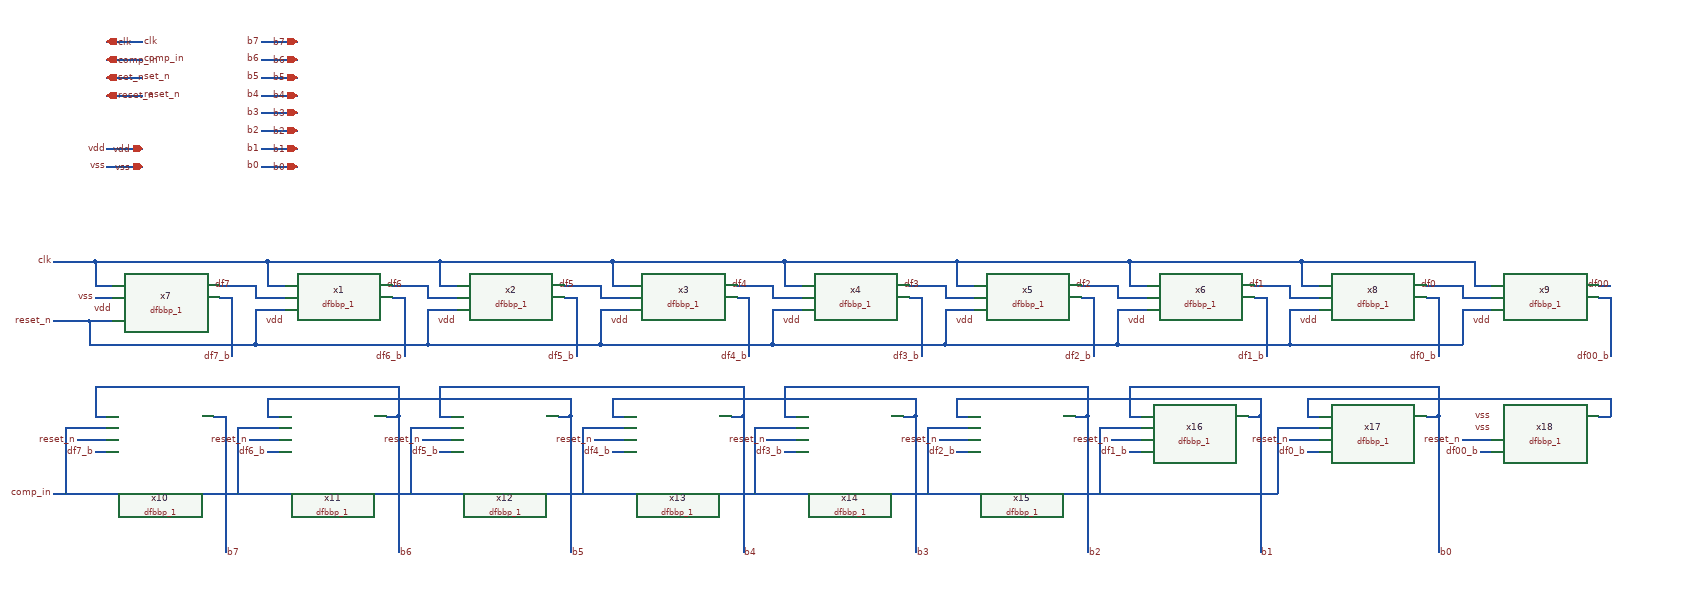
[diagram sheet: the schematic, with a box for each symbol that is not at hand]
v {xschem version=3.4.6RC file_version=1.2
}
G {}
K {}
V {}
S {}
E {}
N 380 -670 410 -670 {lab=clk}
N 380 -710 380 -670 {lab=clk}
N 380 -710 670 -710 {lab=clk}
N 380 -650 410 -650 {lab=vss}
N 370 -610 410 -610 {lab=#net1}
N 370 -610 370 -570 {lab=#net1}
N 650 -630 700 -630 {lab=#net1}
N 370 -570 650 -570 {lab=#net1}
N 650 -630 650 -570 {lab=#net1}
N 670 -670 700 -670 {lab=clk}
N 670 -710 670 -670 {lab=clk}
N 650 -650 700 -650 {lab=df7}
N 650 -670 650 -650 {lab=df7}
N 590 -670 650 -670 {lab=df7}
N 2100 -630 2150 -630 {lab=#net1}
N 2100 -630 2100 -570 {lab=#net1}
N 2120 -670 2150 -670 {lab=clk}
N 2120 -710 2120 -670 {lab=clk}
N 2100 -650 2150 -650 {lab=df2}
N 2100 -670 2100 -650 {lab=df2}
N 880 -670 940 -670 {lab=df6}
N 2390 -630 2440 -630 {lab=#net1}
N 2390 -630 2390 -570 {lab=#net1}
N 2410 -670 2440 -670 {lab=clk}
N 2410 -710 2410 -670 {lab=clk}
N 2390 -650 2440 -650 {lab=df1}
N 2390 -670 2390 -650 {lab=df1}
N 2330 -670 2390 -670 {lab=df1}
N 2680 -630 2730 -630 {lab=#net1}
N 2680 -630 2680 -570 {lab=#net1}
N 2700 -670 2730 -670 {lab=clk}
N 2700 -710 2700 -670 {lab=clk}
N 2680 -650 2730 -650 {lab=df0}
N 2680 -670 2680 -650 {lab=df0}
N 2620 -670 2680 -670 {lab=df0}
N 670 -710 960 -710 {lab=clk}
N 2120 -710 2410 -710 {lab=clk}
N 2410 -710 2700 -710 {lab=clk}
N 650 -570 940 -570 {lab=#net1}
N 2100 -570 2390 -570 {lab=#net1}
N 2390 -570 2680 -570 {lab=#net1}
N 590 -650 610 -650 {lab=df7_b}
N 610 -650 610 -550 {lab=df7_b}
N 880 -650 900 -650 {lab=df6_b}
N 900 -650 900 -550 {lab=df6_b}
N 2330 -650 2350 -650 {lab=df1_b}
N 2350 -650 2350 -550 {lab=df1_b}
N 2620 -650 2640 -650 {lab=df0_b}
N 2640 -650 2640 -550 {lab=df0_b}
N 2910 -650 2930 -650 {lab=df00_b}
N 2930 -650 2930 -550 {lab=df00_b}
N 2910 -670 2930 -670 {lab=df00}
N 940 -630 990 -630 {lab=#net1}
N 940 -630 940 -570 {lab=#net1}
N 960 -670 990 -670 {lab=clk}
N 960 -710 960 -670 {lab=clk}
N 940 -650 990 -650 {lab=df6}
N 940 -670 940 -650 {lab=df6}
N 1170 -670 1230 -670 {lab=df5}
N 960 -710 1250 -710 {lab=clk}
N 940 -570 1230 -570 {lab=#net1}
N 1170 -650 1190 -650 {lab=df5_b}
N 1190 -650 1190 -550 {lab=df5_b}
N 1230 -630 1280 -630 {lab=#net1}
N 1230 -630 1230 -570 {lab=#net1}
N 1250 -670 1280 -670 {lab=clk}
N 1250 -710 1250 -670 {lab=clk}
N 1230 -650 1280 -650 {lab=df5}
N 1230 -670 1230 -650 {lab=df5}
N 1460 -670 1520 -670 {lab=df4}
N 1250 -710 1540 -710 {lab=clk}
N 1230 -570 1520 -570 {lab=#net1}
N 1460 -650 1480 -650 {lab=df4_b}
N 1480 -650 1480 -550 {lab=df4_b}
N 1520 -630 1570 -630 {lab=#net1}
N 1520 -630 1520 -570 {lab=#net1}
N 1540 -670 1570 -670 {lab=clk}
N 1540 -710 1540 -670 {lab=clk}
N 1520 -650 1570 -650 {lab=df4}
N 1520 -670 1520 -650 {lab=df4}
N 1750 -670 1810 -670 {lab=df3}
N 1540 -710 1830 -710 {lab=clk}
N 1520 -570 1810 -570 {lab=#net1}
N 1750 -650 1770 -650 {lab=df3_b}
N 1770 -650 1770 -550 {lab=df3_b}
N 1810 -630 1860 -630 {lab=#net1}
N 1810 -630 1810 -570 {lab=#net1}
N 1830 -670 1860 -670 {lab=clk}
N 1830 -710 1830 -670 {lab=clk}
N 1810 -650 1860 -650 {lab=df3}
N 1810 -670 1810 -650 {lab=df3}
N 2040 -670 2100 -670 {lab=df2}
N 1830 -710 2120 -710 {lab=clk}
N 1810 -570 2100 -570 {lab=#net1}
N 2040 -650 2060 -650 {lab=df2_b}
N 2060 -650 2060 -550 {lab=df2_b}
N 2710 -390 2730 -390 {lab=df00_b}
N 2910 -450 2930 -450 {lab=#net2}
N 2930 -480 2930 -450 {lab=#net2}
N 2420 -450 2440 -450 {lab=#net2}
N 2420 -480 2420 -450 {lab=#net2}
N 2420 -390 2440 -390 {lab=df0_b}
N 2620 -450 2640 -450 {lab=b0}
N 2640 -500 2640 -450 {lab=b0}
N 2120 -500 2120 -450 {lab=b0}
N 2120 -450 2140 -450 {lab=b0}
N 2120 -500 2640 -500 {lab=b0}
N 2320 -450 2340 -450 {lab=b1}
N 2340 -480 2340 -450 {lab=b1}
N 1830 -450 1850 -450 {lab=b1}
N 1830 -480 1830 -450 {lab=b1}
N 1830 -480 2340 -480 {lab=b1}
N 2030 -450 2050 -450 {lab=b2}
N 2050 -500 2050 -450 {lab=b2}
N 1540 -450 1560 -450 {lab=b2}
N 1540 -500 1540 -450 {lab=b2}
N 1540 -500 2050 -500 {lab=b2}
N 1540 -390 1560 -390 {lab=df3_b}
N 1830 -390 1850 -390 {lab=df2_b}
N 2120 -390 2140 -390 {lab=df1_b}
N 1490 -430 1490 -320 {lab=comp_in}
N 1780 -430 1780 -320 {lab=comp_in}
N 1740 -450 1760 -450 {lab=b3}
N 1480 -320 1770 -320 {lab=comp_in}
N 2070 -430 2070 -320 {lab=comp_in}
N 1770 -320 2060 -320 {lab=comp_in}
N 2370 -430 2370 -320 {lab=comp_in}
N 2060 -320 2360 -320 {lab=comp_in}
N 1250 -450 1270 -450 {lab=b3}
N 1250 -480 1250 -450 {lab=b3}
N 1250 -480 1760 -480 {lab=b3}
N 1450 -450 1470 -450 {lab=b4}
N 1470 -500 1470 -450 {lab=b4}
N 960 -450 980 -450 {lab=b4}
N 960 -500 960 -450 {lab=b4}
N 960 -500 1470 -500 {lab=b4}
N 960 -390 980 -390 {lab=df5_b}
N 1250 -390 1270 -390 {lab=df4_b}
N 1200 -430 1200 -320 {lab=comp_in}
N 1160 -450 1180 -450 {lab=b5}
N 900 -320 1190 -320 {lab=comp_in}
N 1760 -480 1760 -450 {lab=b3}
N 1190 -320 1480 -320 {lab=comp_in}
N 910 -430 910 -320 {lab=comp_in}
N 670 -450 690 -450 {lab=b5}
N 670 -480 670 -450 {lab=b5}
N 670 -480 1180 -480 {lab=b5}
N 870 -450 890 -450 {lab=b6}
N 890 -500 890 -450 {lab=b6}
N 380 -450 400 -450 {lab=b6}
N 380 -500 380 -450 {lab=b6}
N 380 -500 890 -500 {lab=b6}
N 380 -390 400 -390 {lab=df7_b}
N 670 -390 690 -390 {lab=df6_b}
N 330 -430 330 -320 {lab=comp_in}
N 310 -320 320 -320 {lab=comp_in}
N 580 -450 600 -450 {lab=b7}
N 320 -320 610 -320 {lab=comp_in}
N 1180 -480 1180 -450 {lab=b5}
N 610 -320 900 -320 {lab=comp_in}
N 620 -430 620 -320 {lab=comp_in}
N 640 -410 690 -410 {lab=reset_n}
N 620 -430 690 -430 {lab=comp_in}
N 600 -450 600 -220 {lab=b7}
N 350 -410 400 -410 {lab=reset_n}
N 330 -430 400 -430 {lab=comp_in}
N 310 -610 370 -610 {lab=#net1}
N 310 -710 380 -710 {lab=clk}
N 930 -410 980 -410 {lab=reset_n}
N 910 -430 980 -430 {lab=comp_in}
N 890 -450 890 -220 {lab=b6}
N 1180 -450 1180 -220 {lab=b5}
N 1220 -410 1270 -410 {lab=reset_n}
N 1200 -430 1270 -430 {lab=comp_in}
N 1510 -410 1560 -410 {lab=reset_n}
N 1490 -430 1560 -430 {lab=comp_in}
N 1470 -450 1470 -220 {lab=b4}
N 1800 -410 1850 -410 {lab=reset_n}
N 1780 -430 1850 -430 {lab=comp_in}
N 1760 -450 1760 -220 {lab=b3}
N 2050 -450 2050 -220 {lab=b2}
N 2090 -410 2140 -410 {lab=reset_n}
N 2070 -430 2140 -430 {lab=comp_in}
N 2340 -450 2340 -220 {lab=b1}
N 2390 -410 2440 -410 {lab=reset_n}
N 2370 -430 2440 -430 {lab=comp_in}
N 2680 -410 2730 -410 {lab=reset_n}
N 2640 -450 2640 -220 {lab=b0}
N 2360 -320 2370 -320 {lab=comp_in}
N 2420 -480 2930 -480 {lab=#net2}
N 660 -1080 720 -1080 {lab=b7}
N 660 -1050 720 -1050 {lab=b6}
N 660 -1020 720 -1020 {lab=b5}
N 660 -990 720 -990 {lab=b4}
N 660 -960 720 -960 {lab=b3}
N 660 -930 720 -930 {lab=b2}
N 660 -900 720 -900 {lab=b1}
N 660 -870 720 -870 {lab=b0}
N 400 -1080 460 -1080 {lab=clk}
N 400 -1050 460 -1050 {lab=comp_in}
N 400 -1020 460 -1020 {lab=set_n}
N 400 -990 460 -990 {lab=reset_n}
N 400 -900 460 -900 {lab=vdd}
N 400 -870 460 -870 {lab=vss}
C {sky130_stdcells/dfbbp_1.sym} 500 -640 0 0 {name=x7 VGND=vss VNB=vss VPB=vdd VPWR=vdd prefix=sky130_fd_sc_hd__ }
C {lab_pin.sym} 610 -550 0 0 {name=p21 sig_type=std_logic lab=df7_b}
C {lab_pin.sym} 310 -710 0 0 {name=p22 sig_type=std_logic lab=clk}
C {devices/lab_pin.sym} 380 -650 0 0 {name=p23 lab=vss}
C {lab_pin.sym} 700 -610 0 0 {name=p24 sig_type=std_logic lab=vdd
}
C {lab_pin.sym} 2150 -610 0 0 {name=p26 sig_type=std_logic lab=vdd
}
C {lab_pin.sym} 2440 -610 0 0 {name=p54 sig_type=std_logic lab=vdd
}
C {lab_pin.sym} 2730 -610 0 0 {name=p55 sig_type=std_logic lab=vdd
}
C {lab_pin.sym} 900 -550 0 0 {name=p56 sig_type=std_logic lab=df6_b}
C {lab_pin.sym} 2350 -550 0 0 {name=p57 sig_type=std_logic lab=df1_b}
C {lab_pin.sym} 2640 -550 0 0 {name=p58 sig_type=std_logic lab=df0_b}
C {lab_pin.sym} 2930 -550 0 0 {name=p59 sig_type=std_logic lab=df00_b}
C {lab_pin.sym} 610 -670 1 0 {name=p61 sig_type=std_logic lab=df7}
C {lab_pin.sym} 900 -670 1 0 {name=p62 sig_type=std_logic lab=df6}
C {lab_pin.sym} 2350 -670 1 0 {name=p64 sig_type=std_logic lab=df1}
C {lab_pin.sym} 2640 -670 1 0 {name=p65 sig_type=std_logic lab=df0}
C {lab_pin.sym} 2930 -670 1 0 {name=p66 sig_type=std_logic lab=df00}
C {lab_pin.sym} 990 -610 0 0 {name=p67 sig_type=std_logic lab=vdd
}
C {lab_pin.sym} 1190 -550 0 0 {name=p68 sig_type=std_logic lab=df5_b}
C {lab_pin.sym} 1190 -670 1 0 {name=p69 sig_type=std_logic lab=df5}
C {lab_pin.sym} 1280 -610 0 0 {name=p70 sig_type=std_logic lab=vdd
}
C {lab_pin.sym} 1480 -550 0 0 {name=p71 sig_type=std_logic lab=df4_b}
C {lab_pin.sym} 1480 -670 1 0 {name=p72 sig_type=std_logic lab=df4}
C {lab_pin.sym} 1570 -610 0 0 {name=p73 sig_type=std_logic lab=vdd
}
C {lab_pin.sym} 1770 -550 0 0 {name=p74 sig_type=std_logic lab=df3_b}
C {lab_pin.sym} 1770 -670 1 0 {name=p75 sig_type=std_logic lab=df3}
C {lab_pin.sym} 1860 -610 0 0 {name=p76 sig_type=std_logic lab=vdd
}
C {lab_pin.sym} 2060 -550 0 0 {name=p77 sig_type=std_logic lab=df2_b}
C {lab_pin.sym} 2060 -670 1 0 {name=p78 sig_type=std_logic lab=df2}
C {lab_pin.sym} 2710 -390 3 0 {name=p79 sig_type=std_logic lab=df00_b}
C {lab_pin.sym} 2420 -390 3 0 {name=p80 sig_type=std_logic lab=df0_b}
C {lab_pin.sym} 2680 -410 3 0 {name=p82 sig_type=std_logic lab=reset_n
}
C {lab_pin.sym} 2390 -410 3 0 {name=p83 sig_type=std_logic lab=reset_n
}
C {lab_pin.sym} 1540 -390 3 0 {name=p84 sig_type=std_logic lab=df3_b}
C {lab_pin.sym} 1830 -390 3 0 {name=p85 sig_type=std_logic lab=df2_b}
C {lab_pin.sym} 2120 -390 3 0 {name=p86 sig_type=std_logic lab=df1_b}
C {lab_pin.sym} 2090 -410 3 0 {name=p87 sig_type=std_logic lab=reset_n
}
C {lab_pin.sym} 1800 -410 3 0 {name=p88 sig_type=std_logic lab=reset_n
}
C {lab_pin.sym} 1510 -410 3 0 {name=p89 sig_type=std_logic lab=reset_n
}
C {lab_pin.sym} 2050 -220 2 0 {name=p90 sig_type=std_logic lab=b2}
C {lab_pin.sym} 1760 -220 2 0 {name=p91 sig_type=std_logic lab=b3}
C {lab_pin.sym} 2340 -220 2 0 {name=p92 sig_type=std_logic lab=b1}
C {lab_pin.sym} 2640 -220 2 0 {name=p93 sig_type=std_logic lab=b0}
C {lab_pin.sym} 310 -320 0 0 {name=p95 sig_type=std_logic lab=comp_in
}
C {lab_pin.sym} 960 -390 3 0 {name=p96 sig_type=std_logic lab=df5_b}
C {lab_pin.sym} 1250 -390 3 0 {name=p97 sig_type=std_logic lab=df4_b}
C {lab_pin.sym} 1220 -410 3 0 {name=p98 sig_type=std_logic lab=reset_n
}
C {lab_pin.sym} 930 -410 3 0 {name=p99 sig_type=std_logic lab=reset_n
}
C {lab_pin.sym} 1470 -220 2 0 {name=p100 sig_type=std_logic lab=b4}
C {lab_pin.sym} 1180 -220 2 0 {name=p101 sig_type=std_logic lab=b5}
C {lab_pin.sym} 380 -390 3 0 {name=p81 sig_type=std_logic lab=df7_b}
C {lab_pin.sym} 670 -390 3 0 {name=p102 sig_type=std_logic lab=df6_b}
C {lab_pin.sym} 640 -410 3 0 {name=p103 sig_type=std_logic lab=reset_n
}
C {lab_pin.sym} 350 -410 3 0 {name=p104 sig_type=std_logic lab=reset_n
}
C {lab_pin.sym} 890 -220 2 0 {name=p105 sig_type=std_logic lab=b6}
C {lab_pin.sym} 600 -220 2 0 {name=p106 sig_type=std_logic lab=b7}
C {iopin.sym} 460 -900 0 0 {name=p1 lab=vdd}
C {iopin.sym} 400 -1080 0 1 {name=p2 lab=clk}
C {iopin.sym} 720 -1080 0 0 {name=p3 lab=b7}
C {iopin.sym} 720 -1050 0 0 {name=p4 lab=b6}
C {iopin.sym} 720 -1020 0 0 {name=p5 lab=b5}
C {iopin.sym} 720 -990 0 0 {name=p6 lab=b4}
C {iopin.sym} 720 -960 0 0 {name=p7 lab=b3}
C {iopin.sym} 720 -930 0 0 {name=p8 lab=b2}
C {iopin.sym} 720 -900 0 0 {name=p9 lab=b1}
C {iopin.sym} 720 -870 0 0 {name=p10 lab=b0}
C {iopin.sym} 400 -1050 0 1 {name=p11 lab=comp_in}
C {iopin.sym} 400 -1020 0 1 {name=p12 lab=set_n}
C {iopin.sym} 460 -870 0 0 {name=p13 lab=vss}
C {iopin.sym} 400 -990 0 1 {name=p14 lab=reset_n}
C {lab_pin.sym} 400 -900 0 0 {name=p15 sig_type=std_logic lab=vdd
}
C {devices/lab_pin.sym} 400 -870 0 0 {name=p16 lab=vss}
C {lab_pin.sym} 660 -1080 2 1 {name=p17 sig_type=std_logic lab=b7}
C {lab_pin.sym} 660 -1050 2 1 {name=p18 sig_type=std_logic lab=b6}
C {lab_pin.sym} 660 -1020 2 1 {name=p19 sig_type=std_logic lab=b5}
C {lab_pin.sym} 660 -990 2 1 {name=p20 sig_type=std_logic lab=b4}
C {lab_pin.sym} 660 -960 2 1 {name=p25 sig_type=std_logic lab=b3}
C {lab_pin.sym} 660 -930 2 1 {name=p27 sig_type=std_logic lab=b2}
C {lab_pin.sym} 660 -900 2 1 {name=p28 sig_type=std_logic lab=b1}
C {lab_pin.sym} 660 -870 2 1 {name=p29 sig_type=std_logic lab=b0}
C {lab_pin.sym} 460 -1080 0 1 {name=p30 sig_type=std_logic lab=clk
}
C {lab_pin.sym} 460 -1050 0 1 {name=p31 sig_type=std_logic lab=comp_in
}
C {lab_pin.sym} 460 -1020 0 1 {name=p32 sig_type=std_logic lab=set_n
}
C {lab_pin.sym} 460 -990 0 1 {name=p33 sig_type=std_logic lab=reset_n
}
C {sky130_stdcells/dfbbp_1.sym} 790 -640 0 0 {name=x1 VGND=vss VNB=vss VPB=vdd VPWR=vdd prefix=sky130_fd_sc_hd__ }
C {sky130_stdcells/dfbbp_1.sym} 1080 -640 0 0 {name=x2 VGND=vss VNB=vss VPB=vdd VPWR=vdd prefix=sky130_fd_sc_hd__ }
C {sky130_stdcells/dfbbp_1.sym} 1370 -640 0 0 {name=x3 VGND=vss VNB=vss VPB=vdd VPWR=vdd prefix=sky130_fd_sc_hd__ }
C {sky130_stdcells/dfbbp_1.sym} 1660 -640 0 0 {name=x4 VGND=vss VNB=vss VPB=vdd VPWR=vdd prefix=sky130_fd_sc_hd__ }
C {sky130_stdcells/dfbbp_1.sym} 1950 -640 0 0 {name=x5 VGND=vss VNB=vss VPB=vdd VPWR=vdd prefix=sky130_fd_sc_hd__ }
C {sky130_stdcells/dfbbp_1.sym} 2240 -640 0 0 {name=x6 VGND=vss VNB=vss VPB=vdd VPWR=vdd prefix=sky130_fd_sc_hd__ }
C {sky130_stdcells/dfbbp_1.sym} 2530 -640 0 0 {name=x8 VGND=vss VNB=vss VPB=vdd VPWR=vdd prefix=sky130_fd_sc_hd__ }
C {sky130_stdcells/dfbbp_1.sym} 2820 -640 0 0 {name=x9 VGND=vss VNB=vss VPB=vdd VPWR=vdd prefix=sky130_fd_sc_hd__ }
C {sky130_stdcells/dfbbp_1.sym} 490 -420 0 0 {name=x10 VGND=vss VNB=vss VPB=vdd VPWR=vdd prefix=sky130_fd_sc_hd__ }
C {sky130_stdcells/dfbbp_1.sym} 780 -420 0 0 {name=x11 VGND=vss VNB=vss VPB=vdd VPWR=vdd prefix=sky130_fd_sc_hd__ }
C {sky130_stdcells/dfbbp_1.sym} 1070 -420 0 0 {name=x12 VGND=vss VNB=vss VPB=vdd VPWR=vdd prefix=sky130_fd_sc_hd__ }
C {sky130_stdcells/dfbbp_1.sym} 1360 -420 0 0 {name=x13 VGND=vss VNB=vss VPB=vdd VPWR=vdd prefix=sky130_fd_sc_hd__ }
C {sky130_stdcells/dfbbp_1.sym} 1650 -420 0 0 {name=x14 VGND=vss VNB=vss VPB=vdd VPWR=vdd prefix=sky130_fd_sc_hd__ }
C {sky130_stdcells/dfbbp_1.sym} 1940 -420 0 0 {name=x15 VGND=vss VNB=vss VPB=vdd VPWR=vdd prefix=sky130_fd_sc_hd__ }
C {sky130_stdcells/dfbbp_1.sym} 2230 -420 0 0 {name=x16 VGND=vss VNB=vss VPB=vdd VPWR=vdd prefix=sky130_fd_sc_hd__ }
C {sky130_stdcells/dfbbp_1.sym} 2530 -420 0 0 {name=x17 VGND=vss VNB=vss VPB=vdd VPWR=vdd prefix=sky130_fd_sc_hd__ }
C {sky130_stdcells/dfbbp_1.sym} 2820 -420 0 0 {name=x18 VGND=vss VNB=vss VPB=vdd VPWR=vdd prefix=sky130_fd_sc_hd__ }
C {lab_pin.sym} 410 -630 0 0 {name=p34 sig_type=std_logic lab=vdd
}
C {lab_pin.sym} 2730 -450 0 0 {name=p35 sig_type=std_logic lab=vss
}
C {lab_pin.sym} 2730 -430 0 0 {name=p36 sig_type=std_logic lab=vss
}
C {lab_pin.sym} 310 -610 0 0 {name=p37 sig_type=std_logic lab=reset_n
}
